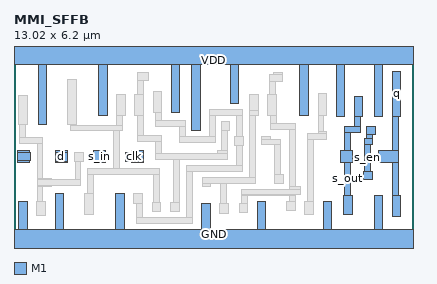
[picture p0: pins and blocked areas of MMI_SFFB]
MACRO MMI_SFFB
	CLASS CORE ;
	FOREIGN MMI_SFFB 0 0 ;
	SIZE 13.02 BY 6.2 ;
	SYMMETRY X Y ;
	SITE CORE1 ;
	PIN d
		DIRECTION input ;
		USE SIGNAL ;
		PORT
			LAYER M1 ;
			RECT 1.36 2.92 1.74 2.98 ;
			LAYER M1 ;
			RECT 1.35 2.64 1.74 2.92 ;
			LAYER M1 ;
			RECT 1.36 2.6 1.74 2.64 ;
		END
		AntennaGateArea 0.3465 ;
	END d
	PIN GND
		DIRECTION inout ;
		USE GROUND ;
		PORT
			LAYER M1 ;
			RECT 0.155 0.42 0.435 1.315 ;
			LAYER M1 ;
			RECT 1.34 0.42 1.62 1.595 ;
			LAYER M1 ;
			RECT 3.31 0.42 3.59 1.575 ;
			LAYER M1 ;
			RECT 6.12 0.42 6.4 1.26 ;
			LAYER M1 ;
			RECT 7.935 0.42 8.215 1.31 ;
			LAYER M1 ;
			RECT 10.085 0.42 10.365 1.335 ;
			LAYER M1 ;
			RECT 11.755 0.42 12.035 1.52 ;
			LAYER M1 ;
			RECT 0 -0.42 13.025 0.42 ;
		END
	END GND
	PIN q
		DIRECTION output ;
		USE SIGNAL ;
		PORT
			LAYER M1 ;
			RECT 12.345 4.105 12.625 5.575 ;
			LAYER M1 ;
			RECT 12.35 2.98 12.545 4.105 ;
			LAYER M1 ;
			RECT 11.905 2.6 12.545 2.98 ;
			LAYER M1 ;
			RECT 12.35 1.52 12.545 2.6 ;
			LAYER M1 ;
			RECT 12.345 0.82 12.625 1.52 ;
		END
		AntennaDiffArea 0.91245 ;
	END q
	PIN s_in
		DIRECTION input ;
		USE SIGNAL ;
		PORT
			LAYER M1 ;
			RECT 2.6 2.6 2.98 2.98 ;
		END
		AntennaGateArea 0.17325 ;
	END s_in
	PIN s_en
		DIRECTION input ;
		USE SIGNAL ;
		PORT
			LAYER M1 ;
			RECT 11.5 3.505 11.78 3.785 ;
			LAYER M1 ;
			RECT 11.5 3.37 11.69 3.505 ;
			LAYER M1 ;
			RECT 11.445 3.175 11.69 3.37 ;
			LAYER M1 ;
			RECT 0.12 2.93 0.5 2.98 ;
			LAYER M1 ;
			RECT 0.12 2.65 0.54 2.93 ;
			LAYER M1 ;
			RECT 0.12 2.6 0.5 2.65 ;
			LAYER M1 ;
			RECT 11.445 2.31 11.64 3.175 ;
			LAYER M1 ;
			RECT 11.415 2.03 11.695 2.31 ;
		END
		AntennaGateArea 0.72675 ;
	END s_en
	PIN VDD
		DIRECTION inout ;
		USE POWER ;
		PORT
			LAYER M1 ;
			RECT 0 5.78 13.025 6.62 ;
			LAYER M1 ;
			RECT 0.785 3.845 1.065 5.78 ;
			LAYER M1 ;
			RECT 2.755 4.115 3.035 5.78 ;
			LAYER M1 ;
			RECT 5.135 4.215 5.415 5.78 ;
			LAYER M1 ;
			RECT 5.805 3.645 6.085 5.78 ;
			LAYER M1 ;
			RECT 7.05 4.52 7.33 5.78 ;
			LAYER M1 ;
			RECT 9.33 4.135 9.61 5.78 ;
			LAYER M1 ;
			RECT 10.515 4.105 10.795 5.78 ;
			LAYER M1 ;
			RECT 11.755 4.105 12.035 5.78 ;
		END
	END VDD
	PIN s_out
		DIRECTION output ;
		USE SIGNAL ;
		PORT
			LAYER M1 ;
			RECT 11.105 4.105 11.385 4.74 ;
			LAYER M1 ;
			RECT 11.105 3.765 11.295 4.105 ;
			LAYER M1 ;
			RECT 10.78 3.575 11.295 3.765 ;
			LAYER M1 ;
			RECT 10.78 2.98 10.975 3.575 ;
			LAYER M1 ;
			RECT 10.665 2.6 11.04 2.98 ;
			LAYER M1 ;
			RECT 10.78 1.52 10.975 2.6 ;
			LAYER M1 ;
			RECT 10.75 0.885 11.03 1.52 ;
		END
		AntennaDiffArea 0.588675 ;
	END s_out
	PIN clk
		DIRECTION input ;
		USE CLOCK ;
		PORT
			LAYER M1 ;
			RECT 3.84 2.92 4.22 2.98 ;
			LAYER M1 ;
			RECT 3.64 2.64 4.22 2.92 ;
			LAYER M1 ;
			RECT 3.84 2.6 4.22 2.64 ;
		END
		AntennaGateArea 0.44625 ;
	END clk
	OBS
		LAYER M1 ;
		RECT 0.155 3.845 0.435 4.78 ;
		LAYER M1 ;
		RECT 1.745 3.845 2.025 5.315 ;
		LAYER M1 ;
		RECT 4.02 5.255 4.39 5.535 ;
		LAYER M1 ;
		RECT 4.02 4.815 4.215 5.255 ;
		LAYER M1 ;
		RECT 3.345 4.115 3.625 4.815 ;
		LAYER M1 ;
		RECT 3.935 4.115 4.215 4.815 ;
		LAYER M1 ;
		RECT 4.545 4.215 4.825 4.915 ;
		LAYER M1 ;
		RECT 0.18 3.41 0.375 3.845 ;
		LAYER M1 ;
		RECT 1.835 3.815 2.025 3.845 ;
		LAYER M1 ;
		RECT 3.345 3.815 3.54 4.115 ;
		LAYER M1 ;
		RECT 1.835 3.625 3.54 3.815 ;
		LAYER M1 ;
		RECT 0.18 3.22 0.945 3.41 ;
		LAYER M1 ;
		RECT 0.755 2.075 0.945 3.22 ;
		LAYER M1 ;
		RECT 1.99 2.64 2.27 2.92 ;
		LAYER M1 ;
		RECT 0.755 2.055 1.215 2.075 ;
		LAYER M1 ;
		RECT 1.995 2.055 2.185 2.64 ;
		LAYER M1 ;
		RECT 3.24 2.4 3.43 3.625 ;
		LAYER M1 ;
		RECT 4.02 3.47 4.215 4.115 ;
		LAYER M1 ;
		RECT 4.625 3.965 4.82 4.215 ;
		LAYER M1 ;
		RECT 4.625 3.77 5.58 3.965 ;
		LAYER M1 ;
		RECT 4.02 3.275 4.8 3.47 ;
		LAYER M1 ;
		RECT 4.61 2.88 4.8 3.275 ;
		LAYER M1 ;
		RECT 5.385 3.445 5.58 3.77 ;
		LAYER M1 ;
		RECT 8.47 5.455 8.75 5.53 ;
		LAYER M1 ;
		RECT 8.34 5.25 8.75 5.455 ;
		LAYER M1 ;
		RECT 8.34 4.815 8.535 5.25 ;
		LAYER M1 ;
		RECT 6.375 4.125 7.44 4.315 ;
		LAYER M1 ;
		RECT 7.695 4.305 7.975 4.815 ;
		LAYER M1 ;
		RECT 6.375 3.445 6.565 4.125 ;
		LAYER M1 ;
		RECT 5.385 3.25 6.565 3.445 ;
		LAYER M1 ;
		RECT 6.765 3.645 7.045 3.925 ;
		LAYER M1 ;
		RECT 6.765 2.97 6.96 3.645 ;
		LAYER M1 ;
		RECT 7.25 3.445 7.44 4.125 ;
		LAYER M1 ;
		RECT 7.685 4.115 7.975 4.305 ;
		LAYER M1 ;
		RECT 8.285 4.115 8.565 4.815 ;
		LAYER M1 ;
		RECT 9.92 4.135 10.2 4.835 ;
		LAYER M1 ;
		RECT 7.205 3.165 7.485 3.445 ;
		LAYER M1 ;
		RECT 6.63 2.88 6.96 2.97 ;
		LAYER M1 ;
		RECT 4.61 2.69 6.96 2.88 ;
		LAYER M1 ;
		RECT 0.755 1.86 2.185 2.055 ;
		LAYER M1 ;
		RECT 2.395 2.21 4.735 2.4 ;
		LAYER M1 ;
		RECT 0.755 1.795 1.215 1.86 ;
		LAYER M1 ;
		RECT 0.755 1.315 0.945 1.795 ;
		LAYER M1 ;
		RECT 2.395 1.595 2.59 2.21 ;
		LAYER M1 ;
		RECT 0.745 0.88 1.025 1.315 ;
		LAYER M1 ;
		RECT 2.31 0.895 2.59 1.595 ;
		LAYER M1 ;
		RECT 3.9 1.26 4.18 1.575 ;
		LAYER M1 ;
		RECT 4.54 1.29 4.735 2.21 ;
		LAYER M1 ;
		RECT 5.195 1.29 5.385 2.69 ;
		LAYER M1 ;
		RECT 7.25 2.49 7.44 3.165 ;
		LAYER M1 ;
		RECT 3.985 0.81 4.18 1.26 ;
		LAYER M1 ;
		RECT 4.515 1.01 4.795 1.29 ;
		LAYER M1 ;
		RECT 5.105 1.01 5.385 1.29 ;
		LAYER M1 ;
		RECT 5.64 2.3 7.44 2.49 ;
		LAYER M1 ;
		RECT 5.64 0.81 5.83 2.3 ;
		LAYER M1 ;
		RECT 7.685 2.1 7.875 4.115 ;
		LAYER M1 ;
		RECT 8.37 3.855 8.565 4.115 ;
		LAYER M1 ;
		RECT 8.37 3.66 9.185 3.855 ;
		LAYER M1 ;
		RECT 8.09 3.36 8.37 3.45 ;
		LAYER M1 ;
		RECT 8.09 3.17 8.69 3.36 ;
		LAYER M1 ;
		RECT 6.22 2.095 7.875 2.1 ;
		LAYER M1 ;
		RECT 6.135 1.91 7.875 2.095 ;
		LAYER M1 ;
		RECT 8.495 2.195 8.69 3.17 ;
		LAYER M1 ;
		RECT 8.495 1.915 8.79 2.195 ;
		LAYER M1 ;
		RECT 6.135 1.815 6.415 1.91 ;
		LAYER M1 ;
		RECT 6.75 1.26 6.94 1.91 ;
		LAYER M1 ;
		RECT 8.99 1.815 9.185 3.66 ;
		LAYER M1 ;
		RECT 9.925 3.62 10.115 4.135 ;
		LAYER M1 ;
		RECT 9.92 3.53 10.2 3.62 ;
		LAYER M1 ;
		RECT 9.57 3.34 10.2 3.53 ;
		LAYER M1 ;
		RECT 8.99 1.71 9.36 1.815 ;
		LAYER M1 ;
		RECT 7.43 1.535 9.36 1.71 ;
		LAYER M1 ;
		RECT 7.43 1.515 9.185 1.535 ;
		LAYER M1 ;
		RECT 3.985 0.62 5.83 0.81 ;
		LAYER M1 ;
		RECT 6.71 0.945 6.99 1.26 ;
		LAYER M1 ;
		RECT 7.43 1.255 7.625 1.515 ;
		LAYER M1 ;
		RECT 8.99 1.31 9.185 1.515 ;
		LAYER M1 ;
		RECT 9.57 1.335 9.765 3.34 ;
		LAYER M1 ;
		RECT 7.345 0.975 7.625 1.255 ;
		LAYER M1 ;
		RECT 8.905 1.03 9.185 1.31 ;
		LAYER M1 ;
		RECT 9.495 0.885 9.775 1.335 ;
	END
END MMI_SFFB
